VERSION 5.7 ;
BUSBITCHARS "[]" ;
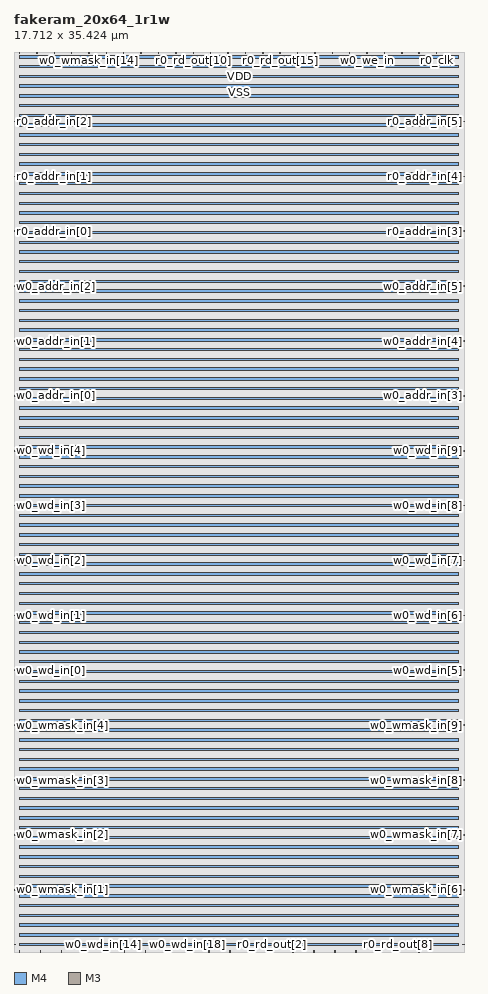
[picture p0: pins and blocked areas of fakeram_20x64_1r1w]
MACRO fakeram_20x64_1r1w
  FOREIGN fakeram_20x64_1r1w 0 0 ;
  SYMMETRY X Y R90 ;
  SIZE 17.712 BY 35.424 ;
  CLASS BLOCK ;
  PIN w0_wmask_in[0]
    DIRECTION INPUT ;
    USE SIGNAL ;
    SHAPE ABUTMENT ;
    PORT
      LAYER M4 ;
      RECT 0.000 0.276 0.072 0.300 ;
    END
  END w0_wmask_in[0]
  PIN w0_wmask_in[1]
    DIRECTION INPUT ;
    USE SIGNAL ;
    SHAPE ABUTMENT ;
    PORT
      LAYER M4 ;
      RECT 0.000 2.436 0.072 2.460 ;
    END
  END w0_wmask_in[1]
  PIN w0_wmask_in[2]
    DIRECTION INPUT ;
    USE SIGNAL ;
    SHAPE ABUTMENT ;
    PORT
      LAYER M4 ;
      RECT 0.000 4.596 0.072 4.620 ;
    END
  END w0_wmask_in[2]
  PIN w0_wmask_in[3]
    DIRECTION INPUT ;
    USE SIGNAL ;
    SHAPE ABUTMENT ;
    PORT
      LAYER M4 ;
      RECT 0.000 6.756 0.072 6.780 ;
    END
  END w0_wmask_in[3]
  PIN w0_wmask_in[4]
    DIRECTION INPUT ;
    USE SIGNAL ;
    SHAPE ABUTMENT ;
    PORT
      LAYER M4 ;
      RECT 0.000 8.916 0.072 8.940 ;
    END
  END w0_wmask_in[4]
  PIN w0_wmask_in[5]
    DIRECTION INPUT ;
    USE SIGNAL ;
    SHAPE ABUTMENT ;
    PORT
      LAYER M4 ;
      RECT 17.640 0.276 17.712 0.300 ;
    END
  END w0_wmask_in[5]
  PIN w0_wmask_in[6]
    DIRECTION INPUT ;
    USE SIGNAL ;
    SHAPE ABUTMENT ;
    PORT
      LAYER M4 ;
      RECT 17.640 2.436 17.712 2.460 ;
    END
  END w0_wmask_in[6]
  PIN w0_wmask_in[7]
    DIRECTION INPUT ;
    USE SIGNAL ;
    SHAPE ABUTMENT ;
    PORT
      LAYER M4 ;
      RECT 17.640 4.596 17.712 4.620 ;
    END
  END w0_wmask_in[7]
  PIN w0_wmask_in[8]
    DIRECTION INPUT ;
    USE SIGNAL ;
    SHAPE ABUTMENT ;
    PORT
      LAYER M4 ;
      RECT 17.640 6.756 17.712 6.780 ;
    END
  END w0_wmask_in[8]
  PIN w0_wmask_in[9]
    DIRECTION INPUT ;
    USE SIGNAL ;
    SHAPE ABUTMENT ;
    PORT
      LAYER M4 ;
      RECT 17.640 8.916 17.712 8.940 ;
    END
  END w0_wmask_in[9]
  PIN w0_wmask_in[10]
    DIRECTION INPUT ;
    USE SIGNAL ;
    SHAPE ABUTMENT ;
    PORT
      LAYER M3 ;
      RECT 0.207 35.370 0.225 35.424 ;
    END
  END w0_wmask_in[10]
  PIN w0_wmask_in[11]
    DIRECTION INPUT ;
    USE SIGNAL ;
    SHAPE ABUTMENT ;
    PORT
      LAYER M3 ;
      RECT 0.891 35.370 0.909 35.424 ;
    END
  END w0_wmask_in[11]
  PIN w0_wmask_in[12]
    DIRECTION INPUT ;
    USE SIGNAL ;
    SHAPE ABUTMENT ;
    PORT
      LAYER M3 ;
      RECT 1.575 35.370 1.593 35.424 ;
    END
  END w0_wmask_in[12]
  PIN w0_wmask_in[13]
    DIRECTION INPUT ;
    USE SIGNAL ;
    SHAPE ABUTMENT ;
    PORT
      LAYER M3 ;
      RECT 2.259 35.370 2.277 35.424 ;
    END
  END w0_wmask_in[13]
  PIN w0_wmask_in[14]
    DIRECTION INPUT ;
    USE SIGNAL ;
    SHAPE ABUTMENT ;
    PORT
      LAYER M3 ;
      RECT 2.943 35.370 2.961 35.424 ;
    END
  END w0_wmask_in[14]
  PIN w0_wmask_in[15]
    DIRECTION INPUT ;
    USE SIGNAL ;
    SHAPE ABUTMENT ;
    PORT
      LAYER M3 ;
      RECT 3.627 35.370 3.645 35.424 ;
    END
  END w0_wmask_in[15]
  PIN w0_wmask_in[16]
    DIRECTION INPUT ;
    USE SIGNAL ;
    SHAPE ABUTMENT ;
    PORT
      LAYER M3 ;
      RECT 4.311 35.370 4.329 35.424 ;
    END
  END w0_wmask_in[16]
  PIN w0_wmask_in[17]
    DIRECTION INPUT ;
    USE SIGNAL ;
    SHAPE ABUTMENT ;
    PORT
      LAYER M3 ;
      RECT 4.995 35.370 5.013 35.424 ;
    END
  END w0_wmask_in[17]
  PIN w0_wmask_in[18]
    DIRECTION INPUT ;
    USE SIGNAL ;
    SHAPE ABUTMENT ;
    PORT
      LAYER M3 ;
      RECT 5.679 35.370 5.697 35.424 ;
    END
  END w0_wmask_in[18]
  PIN w0_wmask_in[19]
    DIRECTION INPUT ;
    USE SIGNAL ;
    SHAPE ABUTMENT ;
    PORT
      LAYER M3 ;
      RECT 6.363 35.370 6.381 35.424 ;
    END
  END w0_wmask_in[19]
  PIN w0_wd_in[0]
    DIRECTION INPUT ;
    USE SIGNAL ;
    SHAPE ABUTMENT ;
    PORT
      LAYER M4 ;
      RECT 0.000 11.076 0.072 11.100 ;
    END
  END w0_wd_in[0]
  PIN w0_wd_in[1]
    DIRECTION INPUT ;
    USE SIGNAL ;
    SHAPE ABUTMENT ;
    PORT
      LAYER M4 ;
      RECT 0.000 13.236 0.072 13.260 ;
    END
  END w0_wd_in[1]
  PIN w0_wd_in[2]
    DIRECTION INPUT ;
    USE SIGNAL ;
    SHAPE ABUTMENT ;
    PORT
      LAYER M4 ;
      RECT 0.000 15.396 0.072 15.420 ;
    END
  END w0_wd_in[2]
  PIN w0_wd_in[3]
    DIRECTION INPUT ;
    USE SIGNAL ;
    SHAPE ABUTMENT ;
    PORT
      LAYER M4 ;
      RECT 0.000 17.556 0.072 17.580 ;
    END
  END w0_wd_in[3]
  PIN w0_wd_in[4]
    DIRECTION INPUT ;
    USE SIGNAL ;
    SHAPE ABUTMENT ;
    PORT
      LAYER M4 ;
      RECT 0.000 19.716 0.072 19.740 ;
    END
  END w0_wd_in[4]
  PIN w0_wd_in[5]
    DIRECTION INPUT ;
    USE SIGNAL ;
    SHAPE ABUTMENT ;
    PORT
      LAYER M4 ;
      RECT 17.640 11.076 17.712 11.100 ;
    END
  END w0_wd_in[5]
  PIN w0_wd_in[6]
    DIRECTION INPUT ;
    USE SIGNAL ;
    SHAPE ABUTMENT ;
    PORT
      LAYER M4 ;
      RECT 17.640 13.236 17.712 13.260 ;
    END
  END w0_wd_in[6]
  PIN w0_wd_in[7]
    DIRECTION INPUT ;
    USE SIGNAL ;
    SHAPE ABUTMENT ;
    PORT
      LAYER M4 ;
      RECT 17.640 15.396 17.712 15.420 ;
    END
  END w0_wd_in[7]
  PIN w0_wd_in[8]
    DIRECTION INPUT ;
    USE SIGNAL ;
    SHAPE ABUTMENT ;
    PORT
      LAYER M4 ;
      RECT 17.640 17.556 17.712 17.580 ;
    END
  END w0_wd_in[8]
  PIN w0_wd_in[9]
    DIRECTION INPUT ;
    USE SIGNAL ;
    SHAPE ABUTMENT ;
    PORT
      LAYER M4 ;
      RECT 17.640 19.716 17.712 19.740 ;
    END
  END w0_wd_in[9]
  PIN w0_wd_in[10]
    DIRECTION INPUT ;
    USE SIGNAL ;
    SHAPE ABUTMENT ;
    PORT
      LAYER M3 ;
      RECT 0.207 0.000 0.225 0.054 ;
    END
  END w0_wd_in[10]
  PIN w0_wd_in[11]
    DIRECTION INPUT ;
    USE SIGNAL ;
    SHAPE ABUTMENT ;
    PORT
      LAYER M3 ;
      RECT 1.035 0.000 1.053 0.054 ;
    END
  END w0_wd_in[11]
  PIN w0_wd_in[12]
    DIRECTION INPUT ;
    USE SIGNAL ;
    SHAPE ABUTMENT ;
    PORT
      LAYER M3 ;
      RECT 1.863 0.000 1.881 0.054 ;
    END
  END w0_wd_in[12]
  PIN w0_wd_in[13]
    DIRECTION INPUT ;
    USE SIGNAL ;
    SHAPE ABUTMENT ;
    PORT
      LAYER M3 ;
      RECT 2.691 0.000 2.709 0.054 ;
    END
  END w0_wd_in[13]
  PIN w0_wd_in[14]
    DIRECTION INPUT ;
    USE SIGNAL ;
    SHAPE ABUTMENT ;
    PORT
      LAYER M3 ;
      RECT 3.519 0.000 3.537 0.054 ;
    END
  END w0_wd_in[14]
  PIN w0_wd_in[15]
    DIRECTION INPUT ;
    USE SIGNAL ;
    SHAPE ABUTMENT ;
    PORT
      LAYER M3 ;
      RECT 4.347 0.000 4.365 0.054 ;
    END
  END w0_wd_in[15]
  PIN w0_wd_in[16]
    DIRECTION INPUT ;
    USE SIGNAL ;
    SHAPE ABUTMENT ;
    PORT
      LAYER M3 ;
      RECT 5.175 0.000 5.193 0.054 ;
    END
  END w0_wd_in[16]
  PIN w0_wd_in[17]
    DIRECTION INPUT ;
    USE SIGNAL ;
    SHAPE ABUTMENT ;
    PORT
      LAYER M3 ;
      RECT 6.003 0.000 6.021 0.054 ;
    END
  END w0_wd_in[17]
  PIN w0_wd_in[18]
    DIRECTION INPUT ;
    USE SIGNAL ;
    SHAPE ABUTMENT ;
    PORT
      LAYER M3 ;
      RECT 6.831 0.000 6.849 0.054 ;
    END
  END w0_wd_in[18]
  PIN w0_wd_in[19]
    DIRECTION INPUT ;
    USE SIGNAL ;
    SHAPE ABUTMENT ;
    PORT
      LAYER M3 ;
      RECT 7.659 0.000 7.677 0.054 ;
    END
  END w0_wd_in[19]
  PIN r0_rd_out[0]
    DIRECTION OUTPUT ;
    USE SIGNAL ;
    SHAPE ABUTMENT ;
    PORT
      LAYER M3 ;
      RECT 8.487 0.000 8.505 0.054 ;
    END
  END r0_rd_out[0]
  PIN r0_rd_out[1]
    DIRECTION OUTPUT ;
    USE SIGNAL ;
    SHAPE ABUTMENT ;
    PORT
      LAYER M3 ;
      RECT 9.315 0.000 9.333 0.054 ;
    END
  END r0_rd_out[1]
  PIN r0_rd_out[2]
    DIRECTION OUTPUT ;
    USE SIGNAL ;
    SHAPE ABUTMENT ;
    PORT
      LAYER M3 ;
      RECT 10.143 0.000 10.161 0.054 ;
    END
  END r0_rd_out[2]
  PIN r0_rd_out[3]
    DIRECTION OUTPUT ;
    USE SIGNAL ;
    SHAPE ABUTMENT ;
    PORT
      LAYER M3 ;
      RECT 10.971 0.000 10.989 0.054 ;
    END
  END r0_rd_out[3]
  PIN r0_rd_out[4]
    DIRECTION OUTPUT ;
    USE SIGNAL ;
    SHAPE ABUTMENT ;
    PORT
      LAYER M3 ;
      RECT 11.799 0.000 11.817 0.054 ;
    END
  END r0_rd_out[4]
  PIN r0_rd_out[5]
    DIRECTION OUTPUT ;
    USE SIGNAL ;
    SHAPE ABUTMENT ;
    PORT
      LAYER M3 ;
      RECT 12.627 0.000 12.645 0.054 ;
    END
  END r0_rd_out[5]
  PIN r0_rd_out[6]
    DIRECTION OUTPUT ;
    USE SIGNAL ;
    SHAPE ABUTMENT ;
    PORT
      LAYER M3 ;
      RECT 13.455 0.000 13.473 0.054 ;
    END
  END r0_rd_out[6]
  PIN r0_rd_out[7]
    DIRECTION OUTPUT ;
    USE SIGNAL ;
    SHAPE ABUTMENT ;
    PORT
      LAYER M3 ;
      RECT 14.283 0.000 14.301 0.054 ;
    END
  END r0_rd_out[7]
  PIN r0_rd_out[8]
    DIRECTION OUTPUT ;
    USE SIGNAL ;
    SHAPE ABUTMENT ;
    PORT
      LAYER M3 ;
      RECT 15.111 0.000 15.129 0.054 ;
    END
  END r0_rd_out[8]
  PIN r0_rd_out[9]
    DIRECTION OUTPUT ;
    USE SIGNAL ;
    SHAPE ABUTMENT ;
    PORT
      LAYER M3 ;
      RECT 15.939 0.000 15.957 0.054 ;
    END
  END r0_rd_out[9]
  PIN r0_rd_out[10]
    DIRECTION OUTPUT ;
    USE SIGNAL ;
    SHAPE ABUTMENT ;
    PORT
      LAYER M3 ;
      RECT 7.047 35.370 7.065 35.424 ;
    END
  END r0_rd_out[10]
  PIN r0_rd_out[11]
    DIRECTION OUTPUT ;
    USE SIGNAL ;
    SHAPE ABUTMENT ;
    PORT
      LAYER M3 ;
      RECT 7.731 35.370 7.749 35.424 ;
    END
  END r0_rd_out[11]
  PIN r0_rd_out[12]
    DIRECTION OUTPUT ;
    USE SIGNAL ;
    SHAPE ABUTMENT ;
    PORT
      LAYER M3 ;
      RECT 8.415 35.370 8.433 35.424 ;
    END
  END r0_rd_out[12]
  PIN r0_rd_out[13]
    DIRECTION OUTPUT ;
    USE SIGNAL ;
    SHAPE ABUTMENT ;
    PORT
      LAYER M3 ;
      RECT 9.099 35.370 9.117 35.424 ;
    END
  END r0_rd_out[13]
  PIN r0_rd_out[14]
    DIRECTION OUTPUT ;
    USE SIGNAL ;
    SHAPE ABUTMENT ;
    PORT
      LAYER M3 ;
      RECT 9.783 35.370 9.801 35.424 ;
    END
  END r0_rd_out[14]
  PIN r0_rd_out[15]
    DIRECTION OUTPUT ;
    USE SIGNAL ;
    SHAPE ABUTMENT ;
    PORT
      LAYER M3 ;
      RECT 10.467 35.370 10.485 35.424 ;
    END
  END r0_rd_out[15]
  PIN r0_rd_out[16]
    DIRECTION OUTPUT ;
    USE SIGNAL ;
    SHAPE ABUTMENT ;
    PORT
      LAYER M3 ;
      RECT 11.151 35.370 11.169 35.424 ;
    END
  END r0_rd_out[16]
  PIN r0_rd_out[17]
    DIRECTION OUTPUT ;
    USE SIGNAL ;
    SHAPE ABUTMENT ;
    PORT
      LAYER M3 ;
      RECT 11.835 35.370 11.853 35.424 ;
    END
  END r0_rd_out[17]
  PIN r0_rd_out[18]
    DIRECTION OUTPUT ;
    USE SIGNAL ;
    SHAPE ABUTMENT ;
    PORT
      LAYER M3 ;
      RECT 12.519 35.370 12.537 35.424 ;
    END
  END r0_rd_out[18]
  PIN r0_rd_out[19]
    DIRECTION OUTPUT ;
    USE SIGNAL ;
    SHAPE ABUTMENT ;
    PORT
      LAYER M3 ;
      RECT 13.203 35.370 13.221 35.424 ;
    END
  END r0_rd_out[19]
  PIN w0_addr_in[0]
    DIRECTION INPUT ;
    USE SIGNAL ;
    SHAPE ABUTMENT ;
    PORT
      LAYER M4 ;
      RECT 0.000 21.876 0.072 21.900 ;
    END
  END w0_addr_in[0]
  PIN w0_addr_in[1]
    DIRECTION INPUT ;
    USE SIGNAL ;
    SHAPE ABUTMENT ;
    PORT
      LAYER M4 ;
      RECT 0.000 24.036 0.072 24.060 ;
    END
  END w0_addr_in[1]
  PIN w0_addr_in[2]
    DIRECTION INPUT ;
    USE SIGNAL ;
    SHAPE ABUTMENT ;
    PORT
      LAYER M4 ;
      RECT 0.000 26.196 0.072 26.220 ;
    END
  END w0_addr_in[2]
  PIN w0_addr_in[3]
    DIRECTION INPUT ;
    USE SIGNAL ;
    SHAPE ABUTMENT ;
    PORT
      LAYER M4 ;
      RECT 17.640 21.876 17.712 21.900 ;
    END
  END w0_addr_in[3]
  PIN w0_addr_in[4]
    DIRECTION INPUT ;
    USE SIGNAL ;
    SHAPE ABUTMENT ;
    PORT
      LAYER M4 ;
      RECT 17.640 24.036 17.712 24.060 ;
    END
  END w0_addr_in[4]
  PIN w0_addr_in[5]
    DIRECTION INPUT ;
    USE SIGNAL ;
    SHAPE ABUTMENT ;
    PORT
      LAYER M4 ;
      RECT 17.640 26.196 17.712 26.220 ;
    END
  END w0_addr_in[5]
  PIN r0_addr_in[0]
    DIRECTION INPUT ;
    USE SIGNAL ;
    SHAPE ABUTMENT ;
    PORT
      LAYER M4 ;
      RECT 0.000 28.356 0.072 28.380 ;
    END
  END r0_addr_in[0]
  PIN r0_addr_in[1]
    DIRECTION INPUT ;
    USE SIGNAL ;
    SHAPE ABUTMENT ;
    PORT
      LAYER M4 ;
      RECT 0.000 30.516 0.072 30.540 ;
    END
  END r0_addr_in[1]
  PIN r0_addr_in[2]
    DIRECTION INPUT ;
    USE SIGNAL ;
    SHAPE ABUTMENT ;
    PORT
      LAYER M4 ;
      RECT 0.000 32.676 0.072 32.700 ;
    END
  END r0_addr_in[2]
  PIN r0_addr_in[3]
    DIRECTION INPUT ;
    USE SIGNAL ;
    SHAPE ABUTMENT ;
    PORT
      LAYER M4 ;
      RECT 17.640 28.356 17.712 28.380 ;
    END
  END r0_addr_in[3]
  PIN r0_addr_in[4]
    DIRECTION INPUT ;
    USE SIGNAL ;
    SHAPE ABUTMENT ;
    PORT
      LAYER M4 ;
      RECT 17.640 30.516 17.712 30.540 ;
    END
  END r0_addr_in[4]
  PIN r0_addr_in[5]
    DIRECTION INPUT ;
    USE SIGNAL ;
    SHAPE ABUTMENT ;
    PORT
      LAYER M4 ;
      RECT 17.640 32.676 17.712 32.700 ;
    END
  END r0_addr_in[5]
  PIN w0_we_in
    DIRECTION INPUT ;
    USE SIGNAL ;
    SHAPE ABUTMENT ;
    PORT
      LAYER M3 ;
      RECT 13.887 35.370 13.905 35.424 ;
    END
  END w0_we_in
  PIN w0_ce_in
    DIRECTION INPUT ;
    USE SIGNAL ;
    SHAPE ABUTMENT ;
    PORT
      LAYER M3 ;
      RECT 14.571 35.370 14.589 35.424 ;
    END
  END w0_ce_in
  PIN w0_clk
    DIRECTION INPUT ;
    USE SIGNAL ;
    SHAPE ABUTMENT ;
    PORT
      LAYER M3 ;
      RECT 15.255 35.370 15.273 35.424 ;
    END
  END w0_clk
  PIN r0_ce_in
    DIRECTION INPUT ;
    USE SIGNAL ;
    SHAPE ABUTMENT ;
    PORT
      LAYER M3 ;
      RECT 15.939 35.370 15.957 35.424 ;
    END
  END r0_ce_in
  PIN r0_clk
    DIRECTION INPUT ;
    USE SIGNAL ;
    SHAPE ABUTMENT ;
    PORT
      LAYER M3 ;
      RECT 16.623 35.370 16.641 35.424 ;
    END
  END r0_clk
  PIN VSS
    DIRECTION INOUT ;
    USE GROUND ;
    PORT
      LAYER M4 ;
      RECT 0.216 0.240 17.496 0.336 ;
      RECT 0.216 1.008 17.496 1.104 ;
      RECT 0.216 1.776 17.496 1.872 ;
      RECT 0.216 2.544 17.496 2.640 ;
      RECT 0.216 3.312 17.496 3.408 ;
      RECT 0.216 4.080 17.496 4.176 ;
      RECT 0.216 4.848 17.496 4.944 ;
      RECT 0.216 5.616 17.496 5.712 ;
      RECT 0.216 6.384 17.496 6.480 ;
      RECT 0.216 7.152 17.496 7.248 ;
      RECT 0.216 7.920 17.496 8.016 ;
      RECT 0.216 8.688 17.496 8.784 ;
      RECT 0.216 9.456 17.496 9.552 ;
      RECT 0.216 10.224 17.496 10.320 ;
      RECT 0.216 10.992 17.496 11.088 ;
      RECT 0.216 11.760 17.496 11.856 ;
      RECT 0.216 12.528 17.496 12.624 ;
      RECT 0.216 13.296 17.496 13.392 ;
      RECT 0.216 14.064 17.496 14.160 ;
      RECT 0.216 14.832 17.496 14.928 ;
      RECT 0.216 15.600 17.496 15.696 ;
      RECT 0.216 16.368 17.496 16.464 ;
      RECT 0.216 17.136 17.496 17.232 ;
      RECT 0.216 17.904 17.496 18.000 ;
      RECT 0.216 18.672 17.496 18.768 ;
      RECT 0.216 19.440 17.496 19.536 ;
      RECT 0.216 20.208 17.496 20.304 ;
      RECT 0.216 20.976 17.496 21.072 ;
      RECT 0.216 21.744 17.496 21.840 ;
      RECT 0.216 22.512 17.496 22.608 ;
      RECT 0.216 23.280 17.496 23.376 ;
      RECT 0.216 24.048 17.496 24.144 ;
      RECT 0.216 24.816 17.496 24.912 ;
      RECT 0.216 25.584 17.496 25.680 ;
      RECT 0.216 26.352 17.496 26.448 ;
      RECT 0.216 27.120 17.496 27.216 ;
      RECT 0.216 27.888 17.496 27.984 ;
      RECT 0.216 28.656 17.496 28.752 ;
      RECT 0.216 29.424 17.496 29.520 ;
      RECT 0.216 30.192 17.496 30.288 ;
      RECT 0.216 30.960 17.496 31.056 ;
      RECT 0.216 31.728 17.496 31.824 ;
      RECT 0.216 32.496 17.496 32.592 ;
      RECT 0.216 33.264 17.496 33.360 ;
      RECT 0.216 34.032 17.496 34.128 ;
      RECT 0.216 34.800 17.496 34.896 ;
    END
  END VSS
  PIN VDD
    DIRECTION INOUT ;
    USE POWER ;
    PORT
      LAYER M4 ;
      RECT 0.216 0.624 17.496 0.720 ;
      RECT 0.216 1.392 17.496 1.488 ;
      RECT 0.216 2.160 17.496 2.256 ;
      RECT 0.216 2.928 17.496 3.024 ;
      RECT 0.216 3.696 17.496 3.792 ;
      RECT 0.216 4.464 17.496 4.560 ;
      RECT 0.216 5.232 17.496 5.328 ;
      RECT 0.216 6.000 17.496 6.096 ;
      RECT 0.216 6.768 17.496 6.864 ;
      RECT 0.216 7.536 17.496 7.632 ;
      RECT 0.216 8.304 17.496 8.400 ;
      RECT 0.216 9.072 17.496 9.168 ;
      RECT 0.216 9.840 17.496 9.936 ;
      RECT 0.216 10.608 17.496 10.704 ;
      RECT 0.216 11.376 17.496 11.472 ;
      RECT 0.216 12.144 17.496 12.240 ;
      RECT 0.216 12.912 17.496 13.008 ;
      RECT 0.216 13.680 17.496 13.776 ;
      RECT 0.216 14.448 17.496 14.544 ;
      RECT 0.216 15.216 17.496 15.312 ;
      RECT 0.216 15.984 17.496 16.080 ;
      RECT 0.216 16.752 17.496 16.848 ;
      RECT 0.216 17.520 17.496 17.616 ;
      RECT 0.216 18.288 17.496 18.384 ;
      RECT 0.216 19.056 17.496 19.152 ;
      RECT 0.216 19.824 17.496 19.920 ;
      RECT 0.216 20.592 17.496 20.688 ;
      RECT 0.216 21.360 17.496 21.456 ;
      RECT 0.216 22.128 17.496 22.224 ;
      RECT 0.216 22.896 17.496 22.992 ;
      RECT 0.216 23.664 17.496 23.760 ;
      RECT 0.216 24.432 17.496 24.528 ;
      RECT 0.216 25.200 17.496 25.296 ;
      RECT 0.216 25.968 17.496 26.064 ;
      RECT 0.216 26.736 17.496 26.832 ;
      RECT 0.216 27.504 17.496 27.600 ;
      RECT 0.216 28.272 17.496 28.368 ;
      RECT 0.216 29.040 17.496 29.136 ;
      RECT 0.216 29.808 17.496 29.904 ;
      RECT 0.216 30.576 17.496 30.672 ;
      RECT 0.216 31.344 17.496 31.440 ;
      RECT 0.216 32.112 17.496 32.208 ;
      RECT 0.216 32.880 17.496 32.976 ;
      RECT 0.216 33.648 17.496 33.744 ;
      RECT 0.216 34.416 17.496 34.512 ;
      RECT 0.216 35.184 17.496 35.280 ;
    END
  END VDD
  OBS
    LAYER M1 ;
    RECT 0 0 17.712 35.424 ;
    LAYER M2 ;
    RECT 0 0 17.712 35.424 ;
    LAYER M3 ;
    RECT 0 0 17.712 35.424 ;
    LAYER M4 ;
    RECT 0 0 17.712 35.424 ;
  END
END fakeram_20x64_1r1w

END LIBRARY
